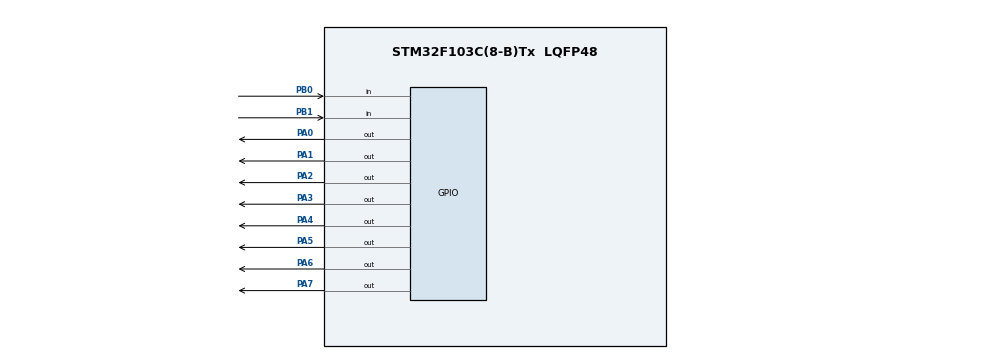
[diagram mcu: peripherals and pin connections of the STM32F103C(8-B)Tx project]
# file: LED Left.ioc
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Mcu.Family=STM32F1
Mcu.Name=STM32F103C(8-B)Tx
Mcu.Package=LQFP48
NVIC.PriorityGroup=NVIC_PRIORITYGROUP_4
PA0-WKUP.Signal=GPIO_Output
PA1.Signal=GPIO_Output
PA13.Mode=Serial_Wire
PA13.Signal=SYS_JTMS-SWDIO
PA14.Mode=Serial_Wire
PA14.Signal=SYS_JTCK-SWCLK
PA2.Signal=GPIO_Output
PA3.Signal=GPIO_Output
PA4.Signal=GPIO_Output
PA5.Signal=GPIO_Output
PA6.Signal=GPIO_Output
PA7.Signal=GPIO_Output
PB0.Signal=GPIO_Input
PB1.Signal=GPIO_Input
PD0-OSC_IN.Mode=HSE-External-Oscillator
PD0-OSC_IN.Signal=RCC_OSC_IN
PD1-OSC_OUT.Mode=HSE-External-Oscillator
PD1-OSC_OUT.Signal=RCC_OSC_OUT
ProjectManager.HeapSize=0x200
ProjectManager.StackSize=0x400
ProjectManager.TargetToolchain=TrueSTUDIO
RCC.APB1Freq_Value=8000000
RCC.APB2Freq_Value=8000000
board=custom

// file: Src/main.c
/**
  ******************************************************************************
  * @file           : main.c
  * @brief          : Main program body
  ******************************************************************************
  ** This notice applies to any and all portions of this file
  * that are not between comment pairs USER CODE BEGIN and
  * USER CODE END. Other portions of this file, whether
  * inserted by the user or by software development tools
  * are owned by their respective copyright owners.
  *
  * COPYRIGHT(c) 2019 STMicroelectronics
  *
  * Redistribution and use in source and binary forms, with or without modification,
  * are permitted provided that the following conditions are met:
  *   1. Redistributions of source code must retain the above copyright notice,
  *      this list of conditions and the following disclaimer.
  *   2. Redistributions in binary form must reproduce the above copyright notice,
  *      this list of conditions and the following disclaimer in the documentation
  *      and/or other materials provided with the distribution.
  *   3. Neither the name of STMicroelectronics nor the names of its contributors
  *      may be used to endorse or promote products derived from this software
  *      without specific prior written permission.
  *
  * THIS SOFTWARE IS PROVIDED BY THE COPYRIGHT HOLDERS AND CONTRIBUTORS "AS IS"
  * AND ANY EXPRESS OR IMPLIED WARRANTIES, INCLUDING, BUT NOT LIMITED TO, THE
  * IMPLIED WARRANTIES OF MERCHANTABILITY AND FITNESS FOR A PARTICULAR PURPOSE ARE
  * DISCLAIMED. IN NO EVENT SHALL THE COPYRIGHT HOLDER OR CONTRIBUTORS BE LIABLE
  * FOR ANY DIRECT, INDIRECT, INCIDENTAL, SPECIAL, EXEMPLARY, OR CONSEQUENTIAL
  * DAMAGES (INCLUDING, BUT NOT LIMITED TO, PROCUREMENT OF SUBSTITUTE GOODS OR
  * SERVICES; LOSS OF USE, DATA, OR PROFITS; OR BUSINESS INTERRUPTION) HOWEVER
  * CAUSED AND ON ANY THEORY OF LIABILITY, WHETHER IN CONTRACT, STRICT LIABILITY,
  * OR TORT (INCLUDING NEGLIGENCE OR OTHERWISE) ARISING IN ANY WAY OUT OF THE USE
  * OF THIS SOFTWARE, EVEN IF ADVISED OF THE POSSIBILITY OF SUCH DAMAGE.
  *
  ******************************************************************************
  */
#include "main.h"
#include "stm32f1xx_hal.h"
#include <stdio.h>

/* USER CODE BEGIN PV */
/* Private variables ---------------------------------------------------------*/

/* USER CODE END PV */

void SystemClock_Config(void);
static void MX_GPIO_Init(void);

/* USER CODE BEGIN PFP */
/* Private function prototypes -----------------------------------------------*/
void shiftClock(void);
void LatchClock(void);
void bytedatawrite(uint8_t data);

#define set_bit(bit)
#define clear_bit(bit)

#define DATA 		GPIO_PIN_0
#define LATCH_CLOCK GPIO_PIN_1
#define SHIFT_CLOCK	GPIO_PIN_2
#define DATAPORT	GPIOA
/* USER CODE END PFP */

int main(void)
{

  /* MCU Configuration----------------------------------------------------------*/

  /* Reset of all peripherals, Initializes the Flash interface and the Systick. */
  HAL_Init();

  /* Configure the system clock */
  SystemClock_Config();

  /* Initialize all configured peripherals */
  MX_GPIO_Init();

  /* Infinite loop */
  /* USER CODE BEGIN WHILE */
  int flag = 0;
  int count=1;

  while (1)
  {

	/* USER CODE END WHILE */

  /* USER CODE BEGIN 3 */

	if(HAL_GPIO_ReadPin(GPIOB, GPIO_PIN_0) == 0)
	  		  flag = 0;

	  else if(HAL_GPIO_ReadPin(GPIOB, GPIO_PIN_1) == 0)
	  		  flag = 1;

	  if(flag==1)
	  {
		  if(count>7)
			  count = -1;
		  count++;
	  }

	  if(flag==0)
	  {
		  if(count<0)
			  count = 8;
		  count--;
	  }

	  bytedatawrite(1<<count);
	  HAL_Delay(300);
  }
  /* USER CODE END 3 */

}

void SystemClock_Config(void)
{

  RCC_OscInitTypeDef RCC_OscInitStruct;
  RCC_ClkInitTypeDef RCC_ClkInitStruct;

    /**Initializes the CPU, AHB and APB busses clocks
    */
  RCC_OscInitStruct.OscillatorType = RCC_OSCILLATORTYPE_HSE;
  RCC_OscInitStruct.HSEState = RCC_HSE_ON;
  RCC_OscInitStruct.HSEPredivValue = RCC_HSE_PREDIV_DIV1;
  RCC_OscInitStruct.HSIState = RCC_HSI_ON;
  RCC_OscInitStruct.PLL.PLLState = RCC_PLL_ON;
  RCC_OscInitStruct.PLL.PLLSource = RCC_PLLSOURCE_HSE;
  RCC_OscInitStruct.PLL.PLLMUL = RCC_PLL_MUL9;
  if (HAL_RCC_OscConfig(&RCC_OscInitStruct) != HAL_OK)
  {
    _Error_Handler(__FILE__, __LINE__);
  }

    /**Initializes the CPU, AHB and APB busses clocks
    */
  RCC_ClkInitStruct.ClockType = RCC_CLOCKTYPE_HCLK|RCC_CLOCKTYPE_SYSCLK
                              |RCC_CLOCKTYPE_PCLK1|RCC_CLOCKTYPE_PCLK2;
  RCC_ClkInitStruct.SYSCLKSource = RCC_SYSCLKSOURCE_PLLCLK;
  RCC_ClkInitStruct.AHBCLKDivider = RCC_SYSCLK_DIV1;
  RCC_ClkInitStruct.APB1CLKDivider = RCC_HCLK_DIV2;
  RCC_ClkInitStruct.APB2CLKDivider = RCC_HCLK_DIV1;

  if (HAL_RCC_ClockConfig(&RCC_ClkInitStruct, FLASH_LATENCY_2) != HAL_OK)
  {
    _Error_Handler(__FILE__, __LINE__);
  }

    /**Configure the Systick interrupt time
    */
  HAL_SYSTICK_Config(HAL_RCC_GetHCLKFreq()/1000);

    /**Configure the Systick
    */
  HAL_SYSTICK_CLKSourceConfig(SYSTICK_CLKSOURCE_HCLK);

  /* SysTick_IRQn interrupt configuration */
  HAL_NVIC_SetPriority(SysTick_IRQn, 0, 0);
}

/** Configure pins as
        * Analog
        * Input
        * Output
        * EVENT_OUT
        * EXTI
*/
static void MX_GPIO_Init(void)
{

  GPIO_InitTypeDef GPIO_InitStruct;

  /* GPIO Ports Clock Enable */
  __HAL_RCC_GPIOC_CLK_ENABLE();
  __HAL_RCC_GPIOD_CLK_ENABLE();
  __HAL_RCC_GPIOA_CLK_ENABLE();
  __HAL_RCC_GPIOB_CLK_ENABLE();

  /*Configure GPIO pin Output Level */
  HAL_GPIO_WritePin(GPIOC, GPIO_PIN_13, GPIO_PIN_RESET);

  /*Configure GPIO pin Output Level */
  HAL_GPIO_WritePin(GPIOA, GPIO_PIN_0|GPIO_PIN_1|GPIO_PIN_2, GPIO_PIN_RESET);

  /*Configure GPIO pin : PC13 */
  GPIO_InitStruct.Pin = GPIO_PIN_13;
  GPIO_InitStruct.Mode = GPIO_MODE_OUTPUT_PP;
  GPIO_InitStruct.Pull = GPIO_NOPULL;
  GPIO_InitStruct.Speed = GPIO_SPEED_FREQ_LOW;
  HAL_GPIO_Init(GPIOC, &GPIO_InitStruct);

  /*Configure GPIO pins : PA0 PA1 PA2 */
  GPIO_InitStruct.Pin = GPIO_PIN_0|GPIO_PIN_1|GPIO_PIN_2;
  GPIO_InitStruct.Mode = GPIO_MODE_OUTPUT_PP;
  GPIO_InitStruct.Pull = GPIO_NOPULL;
  GPIO_InitStruct.Speed = GPIO_SPEED_FREQ_LOW;
  HAL_GPIO_Init(GPIOA, &GPIO_InitStruct);

  /*Configure GPIO pins : PB0 PB1 */
  GPIO_InitStruct.Pin = GPIO_PIN_0|GPIO_PIN_1;
  GPIO_InitStruct.Mode = GPIO_MODE_INPUT;
  GPIO_InitStruct.Pull = GPIO_PULLUP;
  HAL_GPIO_Init(GPIOB, &GPIO_InitStruct);

}

/* USER CODE BEGIN 4 */

void shiftClock(void)
{
	HAL_GPIO_WritePin(DATAPORT, SHIFT_CLOCK, GPIO_PIN_SET);
	HAL_GPIO_WritePin(DATAPORT, SHIFT_CLOCK, GPIO_PIN_RESET);
}

void LatchClock(void)
{
	HAL_GPIO_WritePin(DATAPORT, LATCH_CLOCK, GPIO_PIN_SET);
	HAL_GPIO_WritePin(DATAPORT, LATCH_CLOCK, GPIO_PIN_RESET);
}

void bytedatawrite(uint8_t data)
{
	for(uint8_t i=0; i<8; i++)
	{
		if (data & 0x80)
		{
			HAL_GPIO_WritePin(DATAPORT, DATA, GPIO_PIN_RESET);
		}
		else
		{
			HAL_GPIO_WritePin(DATAPORT, DATA, GPIO_PIN_SET);
		}
		shiftClock();
		data = data << 1;
	}
	LatchClock();
}

/* USER CODE END 4 */

void _Error_Handler(char *file, int line)
{
	while(1)
	{
	}
}

/************************ (C) COPYRIGHT STMicroelectronics *****END OF FILE****/
